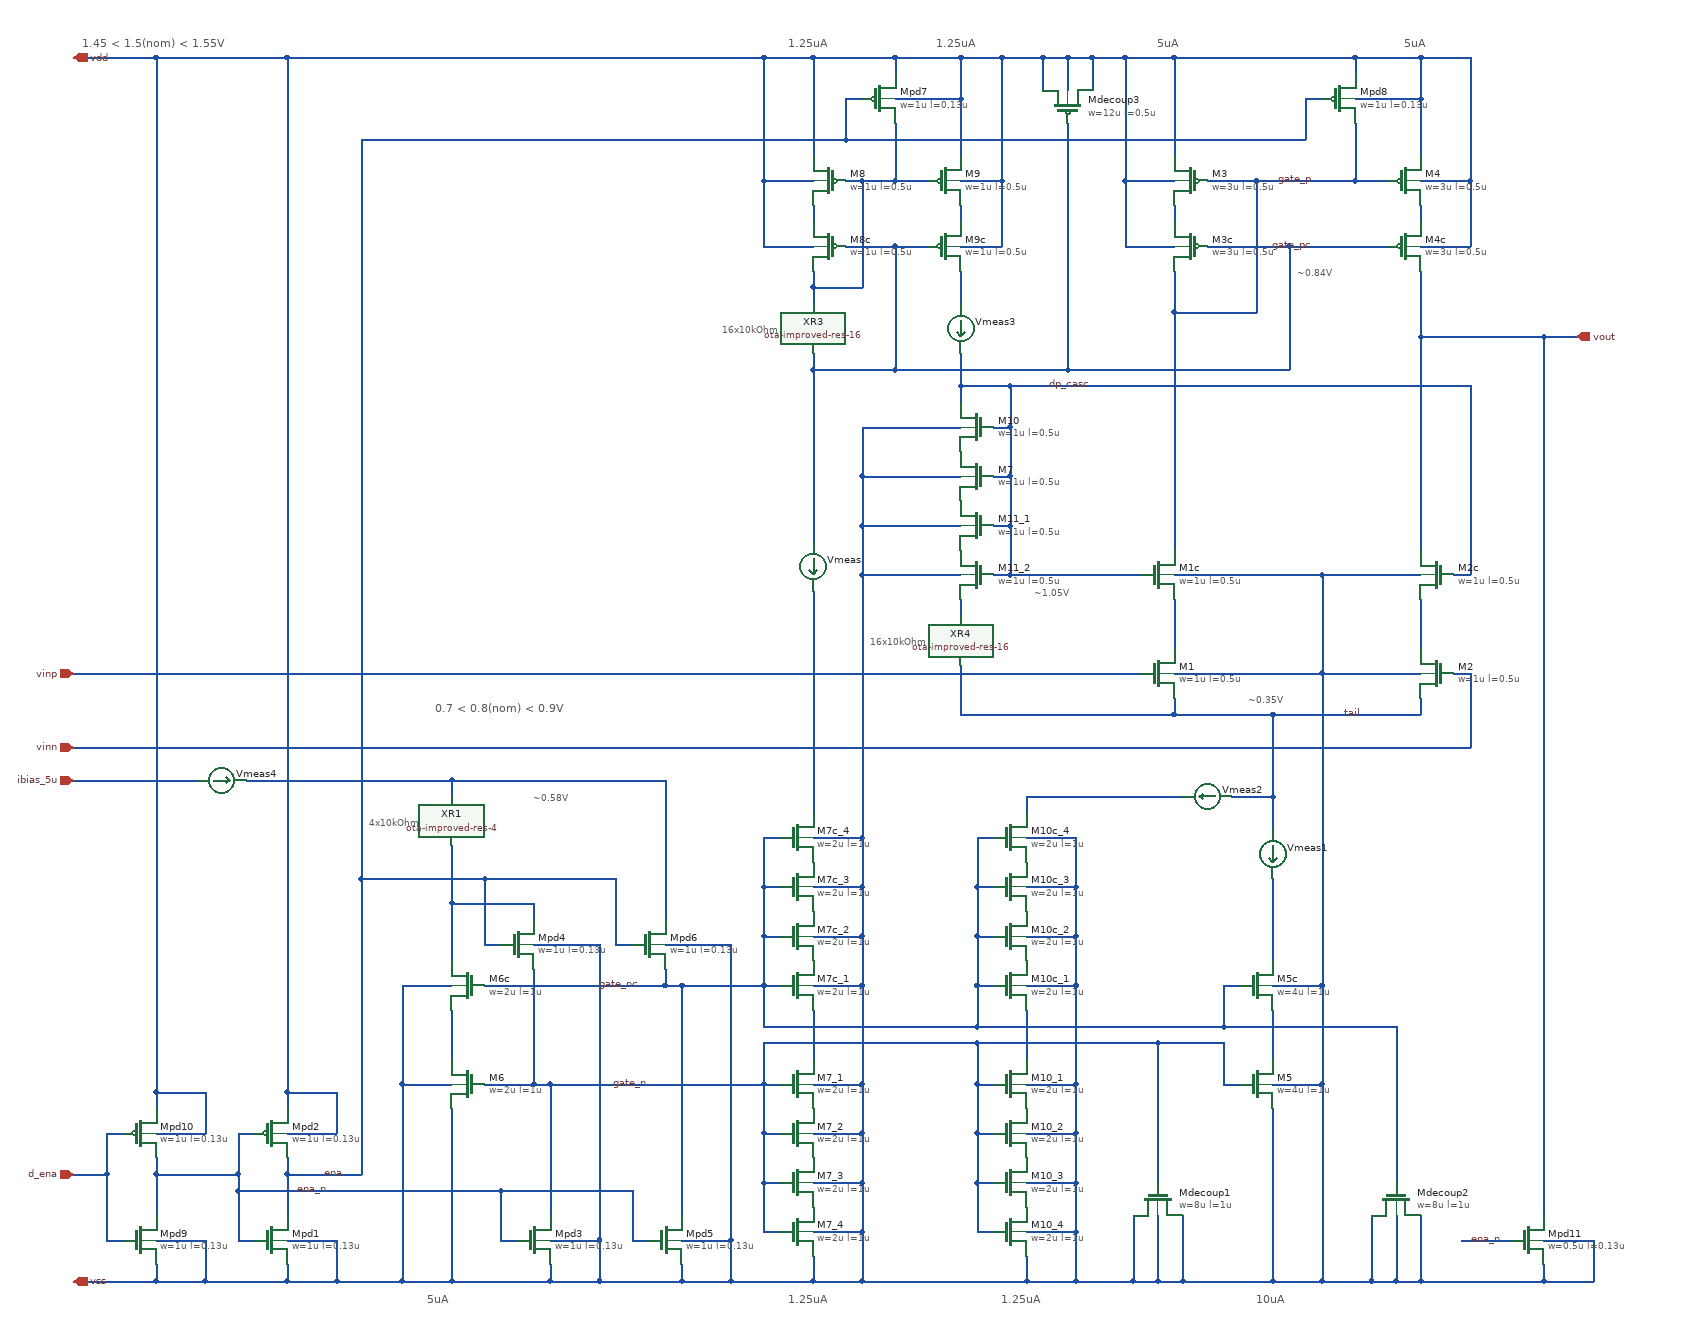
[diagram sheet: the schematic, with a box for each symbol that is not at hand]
v {xschem version=3.4.5 file_version=1.2
}
G {}
K {}
V {}
S {}
E {}
T {1.45 < 1.5(nom) < 1.55V} 160 -1690 0 0 0.4 0.4 {}
T {10uA} 1590 -160 0 0 0.4 0.4 {}
T {0.7 < 0.8(nom) < 0.9V} 590 -880 0 0 0.4 0.4 {}
T {5uA} 580 -160 0 0 0.4 0.4 {}
T {1.25uA} 1020 -160 0 0 0.4 0.4 {}
T {1.25uA} 1020 -1690 0 0 0.4 0.4 {}
T {1.25uA} 1200 -1690 0 0 0.4 0.4 {}
T {5uA} 1470 -1690 0 0 0.4 0.4 {}
T {5uA} 1770 -1690 0 0 0.4 0.4 {}
T {16x10kOhm} 940 -1340 0 0 0.3 0.3 {}
T {4x10kOhm} 510 -740 0 0 0.3 0.3 {}
T {1.25uA} 1280 -160 0 0 0.4 0.4 {}
T {16x10kOhm} 1120 -960 0 0 0.3 0.3 {}
T {~1.05V} 1320 -1020 0 0 0.3 0.3 {}
T {~0.84V} 1640 -1410 0 0 0.3 0.3 {}
T {~0.35V} 1580 -890 0 0 0.3 0.3 {}
T {~0.58V} 710 -770 0 0 0.3 0.3 {}
N 730 -190 730 -170 {
lab=vss}
N 790 -220 790 -170 {
lab=vss}
N 550 -410 610 -410 {
lab=vss}
N 610 -170 730 -170 {
lab=vss}
N 1790 -1660 1850 -1660 {
lab=vdd}
N 470 -170 550 -170 {
lab=vss}
N 410 -190 410 -170 {
lab=vss}
N 310 -170 410 -170 {
lab=vss}
N 350 -220 370 -220 {
lab=ena_n}
N 710 -410 730 -410 {
lab=gate_n}
N 410 -220 470 -220 {
lab=vss}
N 470 -220 470 -170 {
lab=vss}
N 410 -170 470 -170 {
lab=vss}
N 730 -220 790 -220 {
lab=vss}
N 730 -170 790 -170 {
lab=vss}
N 710 -580 790 -580 {
lab=vss}
N 710 -550 710 -410 {
lab=gate_n}
N 650 -410 710 -410 {
lab=gate_n}
N 710 -630 710 -610 {
lab=#net1}
N 610 -630 710 -630 {
lab=#net1}
N 890 -530 990 -530 {
lab=gate_nc}
N 1710 -1660 1790 -1660 {
lab=vdd}
N 890 -190 890 -170 {
lab=vss}
N 790 -170 890 -170 {
lab=vss}
N 890 -220 950 -220 {
lab=vss}
N 950 -220 950 -170 {
lab=vss}
N 890 -170 950 -170 {
lab=vss}
N 830 -220 850 -220 {
lab=ena_n}
N 670 -220 690 -220 {
lab=ena_n}
N 670 -280 830 -280 {
lab=ena_n}
N 610 -780 610 -760 {
lab=#net2}
N 610 -700 610 -630 {
lab=#net1}
N 650 -580 670 -580 {
lab=ena}
N 650 -660 810 -660 {
lab=ena}
N 810 -580 830 -580 {
lab=ena}
N 890 -530 890 -250 {
lab=gate_nc}
N 650 -530 870 -530 {
lab=gate_nc}
N 610 -780 870 -780 {
lab=#net2}
N 870 -780 870 -610 {
lab=#net2}
N 1550 -530 1570 -530 {
lab=gate_nc}
N 990 -460 990 -410 {
lab=gate_n}
N 1550 -460 1550 -410 {
lab=gate_n}
N 1550 -410 1570 -410 {
lab=gate_n}
N 1530 -1510 1590 -1510 {
lab=gate_p}
N 1530 -1430 1630 -1430 {
lab=gate_pc}
N 1710 -1510 1750 -1510 {
lab=gate_p}
N 1710 -1610 1790 -1610 {
lab=vdd}
N 1670 -910 1790 -910 {
lab=vss}
N 870 -580 950 -580 {
lab=vss}
N 1490 -910 1670 -910 {
lab=vss}
N 1150 -1660 1230 -1660 {
lab=vdd}
N 990 -1430 1050 -1430 {
lab=vdd}
N 1150 -1510 1190 -1510 {
lab=#net3}
N 1150 -1430 1190 -1430 {
lab=gate_pc}
N 1650 -1610 1670 -1610 {
lab=ena}
N 1090 -1510 1110 -1510 {
lab=#net3}
N 1050 -1380 1110 -1380 {
lab=#net3}
N 1090 -1430 1150 -1430 {
lab=gate_pc}
N 1150 -1610 1230 -1610 {
lab=vdd}
N 1090 -1610 1110 -1610 {
lab=ena}
N 1230 -1660 1230 -1610 {
lab=vdd}
N 1790 -1660 1790 -1610 {
lab=vdd}
N 1090 -1560 1650 -1560 {
lab=ena}
N 1090 -1610 1090 -1560 {
lab=ena}
N 1650 -1610 1650 -1560 {
lab=ena}
N 1050 -1660 1050 -1540 {
lab=vdd}
N 990 -1660 1050 -1660 {
lab=vdd}
N 990 -1510 1050 -1510 {
lab=vdd}
N 990 -1660 990 -1510 {
lab=vdd}
N 1230 -1510 1280 -1510 {
lab=vdd}
N 1280 -1660 1280 -1510 {
lab=vdd}
N 1230 -1660 1280 -1660 {
lab=vdd}
N 1230 -1610 1230 -1540 {
lab=vdd}
N 990 -1510 990 -1430 {
lab=vdd}
N 1050 -1480 1050 -1460 {
lab=#net4}
N 1230 -1480 1230 -1460 {
lab=#net5}
N 1230 -1430 1280 -1430 {
lab=vdd}
N 1280 -1510 1280 -1430 {
lab=vdd}
N 1050 -1400 1050 -1380 {
lab=#net3}
N 1110 -1510 1110 -1380 {
lab=#net3}
N 1050 -1380 1050 -1360 {
lab=#net3}
N 1050 -1300 1050 -1280 {
lab=gate_pc}
N 1150 -1430 1150 -1280 {
lab=gate_pc}
N 1430 -1510 1490 -1510 {
lab=vdd}
N 1430 -1660 1430 -1510 {
lab=vdd}
N 1490 -1660 1490 -1540 {
lab=vdd}
N 1430 -1660 1490 -1660 {
lab=vdd}
N 1790 -1510 1850 -1510 {
lab=vdd}
N 1850 -1660 1850 -1510 {
lab=vdd}
N 1790 -1610 1790 -1540 {
lab=vdd}
N 1710 -1660 1710 -1640 {
lab=vdd}
N 1490 -1660 1710 -1660 {
lab=vdd}
N 1150 -1660 1150 -1640 {
lab=vdd}
N 1050 -1660 1150 -1660 {
lab=vdd}
N 1850 -1510 1850 -1430 {
lab=vdd}
N 1430 -1510 1430 -1430 {
lab=vdd}
N 1430 -1430 1490 -1430 {
lab=vdd}
N 1790 -1430 1850 -1430 {
lab=vdd}
N 1790 -1480 1790 -1460 {
lab=#net6}
N 1490 -1400 1490 -1350 {
lab=gate_p}
N 1630 -1430 1750 -1430 {
lab=gate_pc}
N 1490 -1030 1670 -1030 {
lab=vss}
N 500 -1560 1090 -1560 {
lab=ena}
N 1050 -1280 1150 -1280 {
lab=gate_pc}
N 1610 -170 1670 -170 {
lab=vss}
N 1470 -460 1550 -460 {
lab=gate_n}
N 730 -410 990 -410 {
lab=gate_n}
N 1050 -530 1110 -530 {
lab=vss}
N 990 -410 1010 -410 {
lab=gate_n}
N 1110 -530 1110 -410 {
lab=vss}
N 1110 -1090 1230 -1090 {
lab=vss}
N 1790 -880 1790 -860 {
lab=tail}
N 1490 -880 1490 -860 {
lab=tail}
N 1610 -860 1790 -860 {
lab=tail}
N 1310 -530 1370 -530 {
lab=vss}
N 1250 -530 1270 -530 {
lab=gate_nc}
N 1250 -410 1270 -410 {
lab=gate_n}
N 1250 -460 1250 -410 {
lab=gate_n}
N 990 -460 1250 -460 {
lab=gate_n}
N 1490 -1480 1490 -1460 {
lab=#net7}
N 1490 -860 1610 -860 {
lab=tail}
N 550 -410 550 -170 {
lab=vss}
N 730 -410 730 -250 {
lab=gate_n}
N 790 -580 790 -220 {
lab=vss}
N 950 -580 950 -220 {
lab=vss}
N 1050 -170 1110 -170 {
lab=vss}
N 990 -410 990 -350 {
lab=gate_n}
N 990 -350 1010 -350 {
lab=gate_n}
N 990 -350 990 -290 {
lab=gate_n}
N 990 -290 1010 -290 {
lab=gate_n}
N 990 -290 990 -230 {
lab=gate_n}
N 990 -230 1010 -230 {
lab=gate_n}
N 1250 -290 1250 -230 {
lab=gate_n}
N 1250 -230 1270 -230 {
lab=gate_n}
N 1250 -290 1270 -290 {
lab=gate_n}
N 1250 -350 1250 -290 {
lab=gate_n}
N 1250 -350 1270 -350 {
lab=gate_n}
N 1250 -410 1250 -350 {
lab=gate_n}
N 1310 -170 1370 -170 {
lab=vss}
N 1670 -410 1670 -170 {
lab=vss}
N 1110 -230 1110 -170 {
lab=vss}
N 1370 -230 1370 -170 {
lab=vss}
N 610 -380 610 -170 {
lab=vss}
N 550 -170 610 -170 {
lab=vss}
N 1050 -200 1050 -170 {
lab=vss}
N 950 -170 1050 -170 {
lab=vss}
N 1050 -230 1110 -230 {
lab=vss}
N 1110 -290 1110 -230 {
lab=vss}
N 1050 -290 1110 -290 {
lab=vss}
N 1110 -350 1110 -290 {
lab=vss}
N 1050 -350 1110 -350 {
lab=vss}
N 1110 -410 1110 -350 {
lab=vss}
N 1050 -410 1110 -410 {
lab=vss}
N 1310 -200 1310 -170 {
lab=vss}
N 1110 -170 1310 -170 {
lab=vss}
N 1310 -230 1370 -230 {
lab=vss}
N 1370 -290 1370 -230 {
lab=vss}
N 1310 -290 1370 -290 {
lab=vss}
N 1370 -350 1370 -290 {
lab=vss}
N 1310 -350 1370 -350 {
lab=vss}
N 1370 -410 1370 -350 {
lab=vss}
N 1310 -410 1370 -410 {
lab=vss}
N 1610 -380 1610 -170 {
lab=vss}
N 1610 -410 1670 -410 {
lab=vss}
N 1610 -530 1670 -530 {
lab=vss}
N 1670 -530 1670 -410 {
lab=vss}
N 1610 -500 1610 -440 {
lab=#net8}
N 1310 -500 1310 -440 {
lab=#net9}
N 1370 -530 1370 -410 {
lab=vss}
N 990 -530 990 -480 {
lab=gate_nc}
N 1050 -500 1050 -440 {
lab=#net10}
N 1110 -590 1110 -530 {
lab=vss}
N 990 -530 1010 -530 {
lab=gate_nc}
N 1250 -480 1550 -480 {
lab=gate_nc}
N 1550 -530 1550 -480 {
lab=gate_nc}
N 1250 -530 1250 -480 {
lab=gate_nc}
N 990 -480 1250 -480 {
lab=gate_nc}
N 1610 -760 1610 -720 {
lab=tail}
N 1250 -590 1250 -530 {
lab=gate_nc}
N 1250 -710 1270 -710 {
lab=gate_nc}
N 1250 -650 1270 -650 {
lab=gate_nc}
N 1250 -710 1250 -650 {
lab=gate_nc}
N 1250 -590 1270 -590 {
lab=gate_nc}
N 1250 -650 1250 -590 {
lab=gate_nc}
N 1310 -710 1370 -710 {
lab=vss}
N 1370 -590 1370 -530 {
lab=vss}
N 1310 -650 1370 -650 {
lab=vss}
N 1370 -710 1370 -650 {
lab=vss}
N 1310 -590 1370 -590 {
lab=vss}
N 1370 -650 1370 -590 {
lab=vss}
N 650 -660 650 -580 {
lab=ena}
N 810 -660 810 -580 {
lab=ena}
N 610 -630 610 -560 {
lab=#net1}
N 550 -530 610 -530 {
lab=vss}
N 550 -530 550 -410 {
lab=vss}
N 610 -500 610 -440 {
lab=#net11}
N 870 -550 870 -530 {
lab=gate_nc}
N 870 -530 890 -530 {
lab=gate_nc}
N 990 -590 990 -530 {
lab=gate_nc}
N 990 -710 1010 -710 {
lab=gate_nc}
N 990 -650 1010 -650 {
lab=gate_nc}
N 990 -710 990 -650 {
lab=gate_nc}
N 990 -590 1010 -590 {
lab=gate_nc}
N 990 -650 990 -590 {
lab=gate_nc}
N 1050 -590 1110 -590 {
lab=vss}
N 1110 -650 1110 -590 {
lab=vss}
N 1050 -650 1110 -650 {
lab=vss}
N 1110 -710 1110 -650 {
lab=vss}
N 1050 -710 1110 -710 {
lab=vss}
N 1610 -660 1610 -560 {
lab=#net12}
N 1560 -760 1610 -760 {
lab=tail}
N 1230 -1400 1230 -1360 {
lab=#net13}
N 1150 -1580 1150 -1510 {
lab=#net3}
N 1110 -1510 1150 -1510 {
lab=#net3}
N 1710 -1580 1710 -1510 {
lab=gate_p}
N 1590 -1510 1710 -1510 {
lab=gate_p}
N 350 -350 370 -350 {
lab=ena_n}
N 410 -400 410 -380 {
lab=vdd}
N 410 -350 470 -350 {
lab=vdd}
N 470 -400 470 -350 {
lab=vdd}
N 410 -400 470 -400 {
lab=vdd}
N 410 -300 410 -250 {
lab=ena}
N 670 -280 670 -220 {
lab=ena_n}
N 830 -280 830 -220 {
lab=ena_n}
N 250 -190 250 -170 {
lab=vss}
N 190 -220 210 -220 {
lab=d_ena}
N 250 -220 310 -220 {
lab=vss}
N 310 -220 310 -170 {
lab=vss}
N 190 -350 210 -350 {
lab=d_ena}
N 250 -400 250 -380 {
lab=vdd}
N 250 -350 310 -350 {
lab=vdd}
N 310 -400 310 -350 {
lab=vdd}
N 250 -400 310 -400 {
lab=vdd}
N 150 -300 190 -300 {
lab=d_ena}
N 190 -300 190 -220 {
lab=d_ena}
N 250 -1660 410 -1660 {
lab=vdd}
N 150 -910 1450 -910 {
lab=vinp}
N 250 -170 310 -170 {
lab=vss}
N 150 -170 250 -170 {
lab=vss}
N 150 -1660 250 -1660 {
lab=vdd}
N 250 -300 350 -300 {
lab=ena_n}
N 250 -300 250 -250 {
lab=ena_n}
N 350 -280 350 -220 {
lab=ena_n}
N 250 -320 250 -300 {
lab=ena_n}
N 350 -350 350 -300 {
lab=ena_n}
N 190 -350 190 -300 {
lab=d_ena}
N 350 -280 670 -280 {
lab=ena_n}
N 350 -300 350 -280 {
lab=ena_n}
N 410 -300 500 -300 {
lab=ena}
N 410 -320 410 -300 {
lab=ena}
N 500 -660 650 -660 {
lab=ena}
N 500 -660 500 -300 {
lab=ena}
N 1830 -1030 1850 -1030 {
lab=dp_casc}
N 1830 -910 1850 -910 {
lab=vinn}
N 150 -820 1850 -820 {
lab=vinn}
N 1940 -1320 1980 -1320 {
lab=vout}
N 1790 -1400 1790 -1320 {
lab=vout}
N 360 -780 610 -780 {
lab=#net2}
N 150 -780 300 -780 {
lab=ibias_5u}
N 1940 -190 1940 -170 {
lab=vss}
N 1940 -220 2000 -220 {
lab=vss}
N 2000 -220 2000 -170 {
lab=vss}
N 1940 -170 2000 -170 {
lab=vss}
N 1790 -1320 1940 -1320 {
lab=vout}
N 1840 -220 1900 -220 {
lab=ena_n}
N 410 -1660 990 -1660 {
lab=vdd}
N 1360 -1280 1630 -1280 {
lab=gate_pc}
N 1290 -1260 1850 -1260 {
lab=dp_casc}
N 1290 -1030 1450 -1030 {
lab=dp_casc}
N 1630 -1430 1630 -1280 {
lab=gate_pc}
N 1490 -1350 1590 -1350 {
lab=gate_p}
N 1590 -1510 1590 -1350 {
lab=gate_p}
N 1310 -760 1310 -740 {
lab=#net14}
N 1310 -760 1500 -760 {
lab=#net14}
N 1230 -860 1490 -860 {
lab=tail}
N 1670 -1030 1670 -910 {
lab=vss}
N 1230 -1300 1230 -1260 {
lab=dp_casc}
N 1290 -1090 1290 -1030 {
lab=dp_casc}
N 1270 -1090 1290 -1090 {
lab=dp_casc}
N 1270 -1030 1290 -1030 {
lab=dp_casc}
N 1050 -1010 1050 -740 {
lab=#net15}
N 1670 -910 1670 -530 {
lab=vss}
N 1110 -1030 1110 -710 {
lab=vss}
N 1610 -860 1610 -760 {
lab=tail}
N 1850 -910 1850 -820 {
lab=vinn}
N 1230 -1000 1230 -980 {
lab=#net16}
N 1230 -920 1230 -860 {
lab=tail}
N 1110 -1030 1230 -1030 {
lab=vss}
N 1110 -1090 1110 -1030 {
lab=vss}
N 1470 -460 1470 -290 {
lab=gate_n}
N 1250 -460 1470 -460 {
lab=gate_n}
N 1550 -480 1760 -480 {
lab=gate_nc}
N 1760 -480 1760 -290 {
lab=gate_nc}
N 1790 -170 1940 -170 {
lab=vss}
N 1500 -170 1610 -170 {
lab=vss}
N 1150 -1280 1360 -1280 {
lab=gate_pc}
N 1390 -1660 1430 -1660 {
lab=vdd}
N 1440 -250 1440 -170 {
lab=vss}
N 1370 -170 1440 -170 {
lab=vss}
N 1470 -250 1470 -170 {
lab=vss}
N 1440 -170 1470 -170 {
lab=vss}
N 1500 -250 1500 -170 {
lab=vss}
N 1470 -170 1500 -170 {
lab=vss}
N 1730 -250 1730 -170 {
lab=vss}
N 1670 -170 1730 -170 {
lab=vss}
N 1760 -250 1760 -170 {
lab=vss}
N 1730 -170 1760 -170 {
lab=vss}
N 1790 -250 1790 -170 {
lab=vss}
N 1760 -170 1790 -170 {
lab=vss}
N 1360 -1580 1360 -1280 {
lab=gate_pc}
N 1330 -1660 1330 -1620 {
lab=vdd}
N 1280 -1660 1330 -1660 {
lab=vdd}
N 1360 -1660 1360 -1620 {
lab=vdd}
N 1330 -1660 1360 -1660 {
lab=vdd}
N 1390 -1660 1390 -1620 {
lab=vdd}
N 1360 -1660 1390 -1660 {
lab=vdd}
N 1050 -1280 1050 -1070 {
lab=gate_pc}
N 500 -1560 500 -660 {
lab=ena}
N 250 -1660 250 -400 {
lab=vdd}
N 410 -1660 410 -400 {
lab=vdd}
N 1850 -1260 1850 -1030 {
lab=dp_casc}
N 1940 -1320 1940 -250 {
lab=vout}
N 1790 -1320 1790 -1060 {
lab=vout}
N 1230 -1260 1230 -1240 {
lab=dp_casc}
N 1110 -1150 1110 -1090 {
lab=vss}
N 1110 -1210 1230 -1210 {
lab=vss}
N 1110 -1150 1230 -1150 {
lab=vss}
N 1110 -1210 1110 -1150 {
lab=vss}
N 1270 -1210 1290 -1210 {
lab=dp_casc}
N 1290 -1150 1290 -1090 {
lab=dp_casc}
N 1270 -1150 1290 -1150 {
lab=dp_casc}
N 1290 -1210 1290 -1150 {
lab=dp_casc}
N 1290 -1260 1290 -1210 {
lab=dp_casc}
N 1230 -1260 1290 -1260 {
lab=dp_casc}
N 1490 -1000 1490 -940 {
lab=#net17}
N 1490 -1350 1490 -1060 {
lab=gate_p}
N 1790 -1000 1790 -940 {
lab=#net18}
N 1670 -1030 1790 -1030 {
lab=vss}
C {devices/title.sym} 160 -30 0 0 {name=l5 author="Copyright 2024 Harald Pretl"}
C {sg13g2_pr/sg13_lv_nmos.sym} 1590 -410 2 1 {name=M5
l=1u
w=4u
ng=2
m=1
model=sg13_lv_nmos
spiceprefix=X
}
C {sg13g2_pr/sg13_lv_pmos.sym} 1770 -1510 0 0 {name=M4
l=0.5u
w=3u
ng=1
m=1
model=sg13_lv_pmos
spiceprefix=X
}
C {sg13g2_pr/sg13_lv_nmos.sym} 1470 -910 2 1 {name=M1
l=0.5u
w=1u
ng=1
m=1
model=sg13_lv_nmos
spiceprefix=X
}
C {sg13g2_pr/sg13_lv_nmos.sym} 1810 -910 2 0 {name=M2
l=0.5u
w=1u
ng=1
m=1
model=sg13_lv_nmos
spiceprefix=X
}
C {sg13g2_pr/sg13_lv_pmos.sym} 1510 -1510 0 1 {name=M3
l=0.5u
w=3u
ng=1
m=1
model=sg13_lv_pmos
spiceprefix=X
}
C {sg13g2_pr/sg13_lv_nmos.sym} 630 -410 2 0 {name=M6
l=1u
w=2u
ng=1
m=1
model=sg13_lv_nmos
spiceprefix=X
}
C {sg13g2_pr/sg13_lv_nmos.sym} 710 -220 2 1 {name=Mpd3
l=0.13u
w=1u
ng=1
m=1
model=sg13_lv_nmos
spiceprefix=X
}
C {ipin.sym} 150 -780 0 0 {name=p1 lab=ibias_5u}
C {iopin.sym} 150 -1660 0 1 {name=p2 lab=vdd}
C {iopin.sym} 150 -170 0 1 {name=p3 lab=vss}
C {ipin.sym} 150 -910 0 0 {name=p4 lab=vinp}
C {ipin.sym} 150 -820 0 0 {name=p5 lab=vinn}
C {opin.sym} 1980 -1320 0 0 {name=p6 lab=vout}
C {sg13g2_pr/sg13_lv_nmos.sym} 390 -220 2 1 {name=Mpd1
l=0.13u
w=1u
ng=1
m=1
model=sg13_lv_nmos
spiceprefix=X
}
C {sg13g2_pr/sg13_lv_pmos.sym} 390 -350 0 0 {name=Mpd2
l=0.13u
w=1u
ng=1
m=1
model=sg13_lv_pmos
spiceprefix=X
}
C {ipin.sym} 150 -300 0 0 {name=p7 lab=d_ena}
C {sg13g2_pr/sg13_lv_nmos.sym} 690 -580 2 1 {name=Mpd4
l=0.13u
w=1u
ng=1
m=1
model=sg13_lv_nmos
spiceprefix=X
}
C {lab_wire.sym} 460 -280 0 0 {name=p8 sig_type=std_logic lab=ena_n}
C {lab_wire.sym} 850 -410 0 0 {name=p9 sig_type=std_logic lab=gate_n}
C {lab_wire.sym} 1660 -1510 0 0 {name=p10 sig_type=std_logic lab=gate_p}
C {lab_wire.sym} 1720 -860 0 0 {name=p11 sig_type=std_logic lab=tail}
C {sg13g2_pr/sg13_lv_nmos.sym} 1590 -530 2 1 {name=M5c
l=1u
w=4u
ng=2
m=1
model=sg13_lv_nmos
spiceprefix=X
}
C {sg13g2_pr/sg13_lv_nmos.sym} 1810 -1030 2 0 {name=M2c
l=0.5u
w=1u
ng=1
m=1
model=sg13_lv_nmos
spiceprefix=X
}
C {sg13g2_pr/sg13_lv_nmos.sym} 1470 -1030 2 1 {name=M1c
l=0.5u
w=1u
ng=1
m=1
model=sg13_lv_nmos
spiceprefix=X
}
C {sg13g2_pr/sg13_lv_nmos.sym} 630 -530 2 0 {name=M6c
l=1u
w=2u
ng=1
m=1
model=sg13_lv_nmos
spiceprefix=X
}
C {sg13g2_pr/sg13_lv_pmos.sym} 1770 -1430 0 0 {name=M4c
l=0.5u
w=3u
ng=1
m=1
model=sg13_lv_pmos
spiceprefix=X
}
C {sg13g2_pr/sg13_lv_pmos.sym} 1510 -1430 0 1 {name=M3c
l=0.5u
w=3u
ng=1
m=1
model=sg13_lv_pmos
spiceprefix=X
}
C {sg13g2_pr/sg13_lv_nmos.sym} 1030 -410 2 1 {name=M7_1
l=1u
w=2u
ng=1
m=1
model=sg13_lv_nmos
spiceprefix=X
}
C {sg13g2_pr/sg13_lv_nmos.sym} 1030 -530 2 1 {name=M7c_1
l=1u
w=2u
ng=1
m=1
model=sg13_lv_nmos
spiceprefix=X
}
C {sg13g2_pr/sg13_lv_nmos.sym} 870 -220 2 1 {name=Mpd5
l=0.13u
w=1u
ng=1
m=1
model=sg13_lv_nmos
spiceprefix=X
}
C {sg13g2_pr/sg13_lv_nmos.sym} 850 -580 2 1 {name=Mpd6
l=0.13u
w=1u
ng=1
m=1
model=sg13_lv_nmos
spiceprefix=X
}
C {lab_wire.sym} 840 -530 0 0 {name=p12 sig_type=std_logic lab=gate_nc}
C {lab_wire.sym} 1660 -1430 0 0 {name=p13 sig_type=std_logic lab=gate_pc}
C {sg13g2_pr/sg13_lv_pmos.sym} 1690 -1610 0 0 {name=Mpd8
l=0.13u
w=1u
ng=1
m=1
model=sg13_lv_pmos
spiceprefix=X
}
C {sg13g2_pr/sg13_lv_pmos.sym} 1070 -1510 0 1 {name=M8
l=0.5u
w=1u
ng=1
m=1
model=sg13_lv_pmos
spiceprefix=X
}
C {sg13g2_pr/sg13_lv_pmos.sym} 1070 -1430 0 1 {name=M8c
l=0.5u
w=1u
ng=1
m=1
model=sg13_lv_pmos
spiceprefix=X
}
C {sg13g2_pr/sg13_lv_pmos.sym} 1210 -1510 0 0 {name=M9
l=0.5u
w=1u
ng=1
m=1
model=sg13_lv_pmos
spiceprefix=X
}
C {sg13g2_pr/sg13_lv_pmos.sym} 1210 -1430 0 0 {name=M9c
l=0.5u
w=1u
ng=1
m=1
model=sg13_lv_pmos
spiceprefix=X
}
C {sg13g2_pr/sg13_lv_pmos.sym} 1130 -1610 0 0 {name=Mpd7
l=0.13u
w=1u
ng=1
m=1
model=sg13_lv_pmos
spiceprefix=X
}
C {sg13g2_pr/sg13_lv_nmos.sym} 1250 -1090 2 0 {name=M11_1
l=0.5u
w=1u
ng=1
m=1
model=sg13_lv_nmos
spiceprefix=X
}
C {lab_wire.sym} 1390 -1260 0 0 {name=p14 sig_type=std_logic lab=dp_casc}
C {sg13g2_pr/sg13_lv_nmos.sym} 1290 -410 2 1 {name=M10_1
l=1u
w=2u
ng=1
m=1
model=sg13_lv_nmos
spiceprefix=X
}
C {sg13g2_pr/sg13_lv_nmos.sym} 1290 -530 2 1 {name=M10c_1
l=1u
w=2u
ng=1
m=1
model=sg13_lv_nmos
spiceprefix=X
}
C {ngspice_probe.sym} 1610 -460 0 0 {name=r5}
C {ngspice_probe.sym} 1490 -960 0 0 {name=r6}
C {ngspice_probe.sym} 1790 -960 0 0 {name=r7}
C {ngspice_probe.sym} 1490 -1460 0 0 {name=r9}
C {ngspice_probe.sym} 1790 -1460 0 0 {name=r10}
C {ngspice_probe.sym} 1100 -1510 0 0 {name=r11}
C {ngspice_probe.sym} 1130 -1430 0 0 {name=r12}
C {ngspice_probe.sym} 1230 -1460 0 0 {name=r13}
C {ngspice_probe.sym} 1050 -1460 0 0 {name=r14}
C {ammeter.sym} 1050 -1040 0 1 {name=Vmeas savecurrent=true spice_ignore=0}
C {ammeter.sym} 1610 -690 0 1 {name=Vmeas1 savecurrent=true spice_ignore=0}
C {sg13g2_pr/sg13_lv_nmos.sym} 1030 -350 2 1 {name=M7_2
l=1u
w=2u
ng=1
m=1
model=sg13_lv_nmos
spiceprefix=X
}
C {sg13g2_pr/sg13_lv_nmos.sym} 1030 -290 2 1 {name=M7_3
l=1u
w=2u
ng=1
m=1
model=sg13_lv_nmos
spiceprefix=X
}
C {sg13g2_pr/sg13_lv_nmos.sym} 1030 -230 2 1 {name=M7_4
l=1u
w=2u
ng=1
m=1
model=sg13_lv_nmos
spiceprefix=X
}
C {sg13g2_pr/sg13_lv_nmos.sym} 1290 -350 2 1 {name=M10_2
l=1u
w=2u
ng=1
m=1
model=sg13_lv_nmos
spiceprefix=X
}
C {sg13g2_pr/sg13_lv_nmos.sym} 1290 -290 2 1 {name=M10_3
l=1u
w=2u
ng=1
m=1
model=sg13_lv_nmos
spiceprefix=X
}
C {sg13g2_pr/sg13_lv_nmos.sym} 1290 -230 2 1 {name=M10_4
l=1u
w=2u
ng=1
m=1
model=sg13_lv_nmos
spiceprefix=X
}
C {sg13g2_pr/sg13_lv_nmos.sym} 1290 -590 2 1 {name=M10c_2
l=1u
w=2u
ng=1
m=1
model=sg13_lv_nmos
spiceprefix=X
}
C {sg13g2_pr/sg13_lv_nmos.sym} 1290 -650 2 1 {name=M10c_3
l=1u
w=2u
ng=1
m=1
model=sg13_lv_nmos
spiceprefix=X
}
C {sg13g2_pr/sg13_lv_nmos.sym} 1290 -710 2 1 {name=M10c_4
l=1u
w=2u
ng=1
m=1
model=sg13_lv_nmos
spiceprefix=X
}
C {sg13g2_pr/sg13_lv_nmos.sym} 1030 -590 2 1 {name=M7c_2
l=1u
w=2u
ng=1
m=1
model=sg13_lv_nmos
spiceprefix=X
}
C {sg13g2_pr/sg13_lv_nmos.sym} 1030 -650 2 1 {name=M7c_3
l=1u
w=2u
ng=1
m=1
model=sg13_lv_nmos
spiceprefix=X}
C {sg13g2_pr/sg13_lv_nmos.sym} 1030 -710 2 1 {name=M7c_4
l=1u
w=2u
ng=1
m=1
model=sg13_lv_nmos
spiceprefix=X
}
C {ammeter.sym} 1530 -760 1 1 {name=Vmeas2 savecurrent=true spice_ignore=0}
C {ammeter.sym} 1230 -1330 0 1 {name=Vmeas3 savecurrent=true spice_ignore=0}
C {sg13g2_pr/sg13_lv_nmos.sym} 230 -220 2 1 {name=Mpd9
l=0.13u
w=1u
ng=1
m=1
model=sg13_lv_nmos
spiceprefix=X}
C {sg13g2_pr/sg13_lv_pmos.sym} 230 -350 0 0 {name=Mpd10
l=0.13u
w=1u
ng=1
m=1
model=sg13_lv_pmos
spiceprefix=X
}
C {lab_wire.sym} 480 -300 0 0 {name=p15 sig_type=std_logic lab=ena}
C {ota-improved-res-16.sym} 1050 -1300 0 0 {name=XR3}
C {ota-improved-res-16.sym} 1230 -920 0 0 {name=XR4}
C {ammeter.sym} 330 -780 3 1 {name=Vmeas4 savecurrent=true spice_ignore=0}
C {ota-improved-res-4.sym} 610 -700 0 0 {name=XR1}
C {ngspice_probe.sym} 610 -460 0 0 {name=r1}
C {sg13g2_pr/sg13_lv_nmos.sym} 1920 -220 2 1 {name=Mpd11
l=0.13u
w=0.5u
ng=1
m=1
model=sg13_lv_nmos
spiceprefix=X
}
C {lab_wire.sym} 1890 -220 0 0 {name=p16 sig_type=std_logic lab=ena_n}
C {sg13g2_pr/sg13_lv_nmos.sym} 1250 -1030 2 0 {name=M11_2
l=0.5u
w=1u
ng=1
m=1
model=sg13_lv_nmos
spiceprefix=X
}
C {sg13g2_pr/sg13_lv_nmos.sym} 1470 -270 3 1 {name=Mdecoup1
l=1u
w=8u
ng=4
m=1
model=sg13_lv_nmos
spiceprefix=X
}
C {sg13g2_pr/sg13_lv_nmos.sym} 1760 -270 3 1 {name=Mdecoup2
l=1u
w=8u
ng=4
m=1
model=sg13_lv_nmos
spiceprefix=X
}
C {sg13g2_pr/sg13_lv_pmos.sym} 1360 -1600 1 1 {name=Mdecoup3
l=0.5u
w=12u
ng=4
m=1
model=sg13_lv_pmos
spiceprefix=X
}
C {sg13g2_pr/sg13_lv_nmos.sym} 1250 -1150 2 0 {name=M7
l=0.5u
w=1u
ng=1
m=1
model=sg13_lv_nmos
spiceprefix=X
}
C {sg13g2_pr/sg13_lv_nmos.sym} 1250 -1210 2 0 {name=M10
l=0.5u
w=1u
ng=1
m=1
model=sg13_lv_nmos
spiceprefix=X
}
C {ngspice_probe.sym} 1230 -990 0 0 {name=r2}
